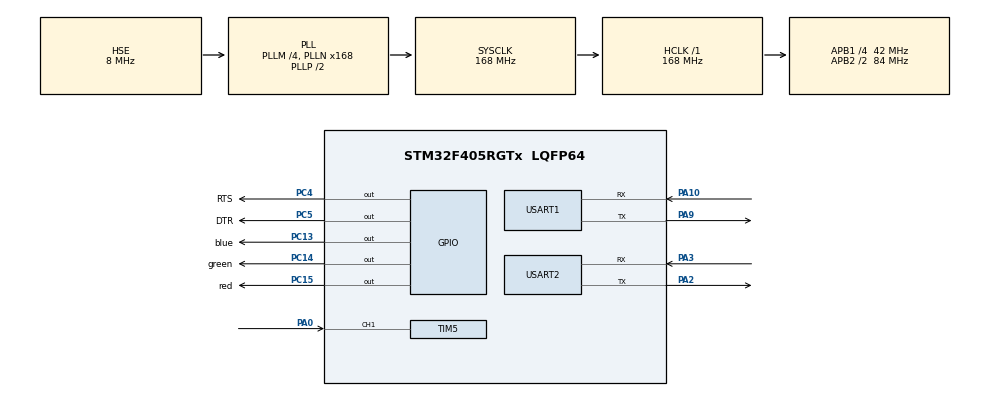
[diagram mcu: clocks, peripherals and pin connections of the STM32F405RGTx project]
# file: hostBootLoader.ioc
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Dma.Request0=USART1_TX
Dma.Request1=USART1_RX
Dma.Request2=USART2_TX
Dma.Request3=USART2_RX
Dma.USART1_RX.1.Direction=DMA_PERIPH_TO_MEMORY
Dma.USART1_RX.1.FIFOMode=DMA_FIFOMODE_DISABLE
Dma.USART1_RX.1.Instance=DMA2_Stream2
Dma.USART1_RX.1.MemDataAlignment=DMA_MDATAALIGN_BYTE
Dma.USART1_RX.1.MemInc=DMA_MINC_ENABLE
Dma.USART1_RX.1.Mode=DMA_NORMAL
Dma.USART1_RX.1.PeriphDataAlignment=DMA_PDATAALIGN_BYTE
Dma.USART1_RX.1.PeriphInc=DMA_PINC_DISABLE
Dma.USART1_RX.1.Priority=DMA_PRIORITY_LOW
Dma.USART1_TX.0.Direction=DMA_MEMORY_TO_PERIPH
Dma.USART1_TX.0.FIFOMode=DMA_FIFOMODE_DISABLE
Dma.USART1_TX.0.Instance=DMA2_Stream7
Dma.USART1_TX.0.MemDataAlignment=DMA_MDATAALIGN_BYTE
Dma.USART1_TX.0.MemInc=DMA_MINC_ENABLE
Dma.USART1_TX.0.Mode=DMA_NORMAL
Dma.USART1_TX.0.PeriphDataAlignment=DMA_PDATAALIGN_BYTE
Dma.USART1_TX.0.PeriphInc=DMA_PINC_DISABLE
Dma.USART1_TX.0.Priority=DMA_PRIORITY_LOW
Dma.USART2_RX.3.Direction=DMA_PERIPH_TO_MEMORY
Dma.USART2_RX.3.FIFOMode=DMA_FIFOMODE_DISABLE
Dma.USART2_RX.3.Instance=DMA1_Stream5
Dma.USART2_RX.3.MemDataAlignment=DMA_MDATAALIGN_BYTE
Dma.USART2_RX.3.MemInc=DMA_MINC_ENABLE
Dma.USART2_RX.3.Mode=DMA_NORMAL
Dma.USART2_RX.3.PeriphDataAlignment=DMA_PDATAALIGN_BYTE
Dma.USART2_RX.3.PeriphInc=DMA_PINC_DISABLE
Dma.USART2_RX.3.Priority=DMA_PRIORITY_HIGH
Dma.USART2_TX.2.Direction=DMA_MEMORY_TO_PERIPH
Dma.USART2_TX.2.FIFOMode=DMA_FIFOMODE_DISABLE
Dma.USART2_TX.2.Instance=DMA1_Stream6
Dma.USART2_TX.2.MemDataAlignment=DMA_MDATAALIGN_BYTE
Dma.USART2_TX.2.MemInc=DMA_MINC_ENABLE
Dma.USART2_TX.2.Mode=DMA_NORMAL
Dma.USART2_TX.2.PeriphDataAlignment=DMA_PDATAALIGN_BYTE
Dma.USART2_TX.2.PeriphInc=DMA_PINC_DISABLE
Dma.USART2_TX.2.Priority=DMA_PRIORITY_HIGH
Mcu.Family=STM32F4
Mcu.Name=STM32F405RGTx
Mcu.Package=LQFP64
NVIC.DMA1_Stream5_IRQn=true\:0\:0\:false\:false\:true\:false\:true
NVIC.DMA1_Stream6_IRQn=true\:0\:0\:false\:false\:true\:false\:true
NVIC.DMA2_Stream2_IRQn=true\:0\:0\:false\:false\:true\:false\:true
NVIC.DMA2_Stream7_IRQn=true\:0\:0\:false\:false\:true\:false\:true
NVIC.PriorityGroup=NVIC_PRIORITYGROUP_4
NVIC.TIM5_IRQn=true\:0\:0\:false\:false\:true\:true\:true
NVIC.USART1_IRQn=true\:0\:0\:false\:false\:true\:true\:true
NVIC.USART2_IRQn=true\:0\:0\:false\:false\:true\:true\:true
PA0-WKUP.Signal=S_TIM5_CH1
PA10.Mode=Asynchronous
PA10.Signal=USART1_RX
PA13.Mode=Serial_Wire
PA13.Signal=SYS_JTMS-SWDIO
PA14.Mode=Serial_Wire
PA14.Signal=SYS_JTCK-SWCLK
PA2.GPIO_ModeDefaultPP=GPIO_MODE_AF_PP
PA2.GPIO_PuPd=GPIO_NOPULL
PA2.GPIO_Speed=GPIO_SPEED_FREQ_VERY_HIGH
PA2.Mode=Asynchronous
PA2.Signal=USART2_TX
PA3.GPIO_ModeDefaultPP=GPIO_MODE_AF_PP
PA3.GPIO_PuPd=GPIO_NOPULL
PA3.GPIO_Speed=GPIO_SPEED_FREQ_VERY_HIGH
PA3.Mode=Asynchronous
PA3.Signal=USART2_RX
PA9.Mode=Asynchronous
PA9.Signal=USART1_TX
PC13-ANTI_TAMP.GPIO_Label=blue
PC13-ANTI_TAMP.GPIO_ModeDefaultOutputPP=GPIO_MODE_OUTPUT_PP
PC13-ANTI_TAMP.GPIO_PuPd=GPIO_NOPULL
PC13-ANTI_TAMP.GPIO_Speed=GPIO_SPEED_FREQ_LOW
PC13-ANTI_TAMP.PinState=GPIO_PIN_SET
PC13-ANTI_TAMP.Signal=GPIO_Output
PC14-OSC32_IN.GPIO_Label=green
PC14-OSC32_IN.GPIO_ModeDefaultOutputPP=GPIO_MODE_OUTPUT_PP
PC14-OSC32_IN.GPIO_PuPd=GPIO_NOPULL
PC14-OSC32_IN.GPIO_Speed=GPIO_SPEED_FREQ_LOW
PC14-OSC32_IN.PinState=GPIO_PIN_SET
PC14-OSC32_IN.Signal=GPIO_Output
PC15-OSC32_OUT.GPIO_Label=red
PC15-OSC32_OUT.GPIO_ModeDefaultOutputPP=GPIO_MODE_OUTPUT_PP
PC15-OSC32_OUT.GPIO_PuPd=GPIO_NOPULL
PC15-OSC32_OUT.GPIO_Speed=GPIO_SPEED_FREQ_LOW
PC15-OSC32_OUT.PinState=GPIO_PIN_SET
PC15-OSC32_OUT.Signal=GPIO_Output
PC4.GPIO_Label=RTS
PC4.GPIO_ModeDefaultOutputPP=GPIO_MODE_OUTPUT_PP
PC4.GPIO_PuPd=GPIO_NOPULL
PC4.GPIO_Speed=GPIO_SPEED_FREQ_VERY_HIGH
PC4.PinState=GPIO_PIN_SET
PC4.Signal=GPIO_Output
PC5.GPIO_Label=DTR
PC5.GPIO_ModeDefaultOutputPP=GPIO_MODE_OUTPUT_PP
PC5.GPIO_PuPd=GPIO_NOPULL
PC5.GPIO_Speed=GPIO_SPEED_FREQ_VERY_HIGH
PC5.PinState=GPIO_PIN_RESET
PC5.Signal=GPIO_Output
PH0-OSC_IN.Mode=HSE-External-Oscillator
PH0-OSC_IN.Signal=RCC_OSC_IN
PH1-OSC_OUT.Mode=HSE-External-Oscillator
PH1-OSC_OUT.Signal=RCC_OSC_OUT
ProjectManager.HeapSize=0x200
ProjectManager.StackSize=0x400
ProjectManager.TargetToolchain=MDK-ARM V5.32
RCC.48MHZClocksFreq_Value=84000000
RCC.AHBFreq_Value=168000000
RCC.APB1CLKDivider=RCC_HCLK_DIV4
RCC.APB1Freq_Value=42000000
RCC.APB1TimFreq_Value=84000000
RCC.APB2CLKDivider=RCC_HCLK_DIV2
RCC.APB2Freq_Value=84000000
RCC.APB2TimFreq_Value=168000000
RCC.CortexFreq_Value=168000000
RCC.HCLKFreq_Value=168000000
RCC.HSE_VALUE=8000000
RCC.HSI_VALUE=16000000
RCC.LSE_VALUE=32768
RCC.PLLM=4
RCC.PLLN=168
RCC.PLLSourceVirtual=RCC_PLLSOURCE_HSE
RCC.SYSCLKFreq_VALUE=168000000
RCC.SYSCLKSource=RCC_SYSCLKSOURCE_PLLCLK
RCC.VCOOutputFreq_Value=336000000
SH.S_TIM5_CH1.0=TIM5_CH1,Input_Capture1_from_TI1
TIM2.Prescaler=83
TIM5.Channel-Input_Capture1_from_TI1=TIM_CHANNEL_1
TIM5.Prescaler=83
USART1.VirtualMode=VM_ASYNC
USART2.Parity=PARITY_EVEN
USART2.VirtualMode=VM_ASYNC
USART2.WordLength=WORDLENGTH_9B
VP_TIM2_VS_ClockSourceINT.Mode=Internal
VP_TIM5_VS_ClockSourceINT.Mode=Internal
board=custom

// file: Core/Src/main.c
/* USER CODE BEGIN Header */
/**
  ******************************************************************************
  * @file           : main.c
  * @brief          : Main program body
  ******************************************************************************
  * @attention
  *
  * <h2><center>&copy; Copyright (c) 2022 STMicroelectronics.
  * All rights reserved.</center></h2>
  *
  * This software component is licensed by ST under BSD 3-Clause license,
  * the "License"; You may not use this file except in compliance with the
  * License. You may obtain a copy of the License at:
  *                        opensource.org/licenses/BSD-3-Clause
  *
  ******************************************************************************
  */
/* USER CODE END Header */
#include "main.h"

/* USER CODE BEGIN Includes */
#include "hostBootLoader.h"
#include "test.h"
/* USER CODE END Includes */

TIM_HandleTypeDef htim2;
TIM_HandleTypeDef htim5;

UART_HandleTypeDef huart1;
UART_HandleTypeDef huart2;
DMA_HandleTypeDef hdma_usart1_tx;
DMA_HandleTypeDef hdma_usart1_rx;
DMA_HandleTypeDef hdma_usart2_tx;
DMA_HandleTypeDef hdma_usart2_rx;

void SystemClock_Config(void);
static void MX_GPIO_Init(void);
static void MX_DMA_Init(void);
static void MX_TIM2_Init(void);
static void MX_USART1_UART_Init(void);
static void MX_USART2_UART_Init(void);
static void MX_TIM5_Init(void);

int main(void)
{

  /* MCU Configuration--------------------------------------------------------*/

  /* Reset of all peripherals, Initializes the Flash interface and the Systick. */
  HAL_Init();

  /* Configure the system clock */
  SystemClock_Config();

  /* Initialize all configured peripherals */
  MX_GPIO_Init();
  MX_DMA_Init();
  MX_TIM2_Init();
  MX_USART1_UART_Init();
  MX_USART2_UART_Init();
  MX_TIM5_Init();
  /* USER CODE BEGIN 2 */
    hostBootLoader_init(&huart2, &huart1);
  /* USER CODE END 2 */

  /* Infinite loop */
  /* USER CODE BEGIN WHILE */
  while (1)
  {

      hostBootLoader_process();
    /* USER CODE END WHILE */

  }
}

void SystemClock_Config(void)
{
  RCC_OscInitTypeDef RCC_OscInitStruct = {0};
  RCC_ClkInitTypeDef RCC_ClkInitStruct = {0};

  /** Configure the main internal regulator output voltage
  */
  __HAL_RCC_PWR_CLK_ENABLE();
  __HAL_PWR_VOLTAGESCALING_CONFIG(PWR_REGULATOR_VOLTAGE_SCALE1);
  /** Initializes the RCC Oscillators according to the specified parameters
  * in the RCC_OscInitTypeDef structure.
  */
  RCC_OscInitStruct.OscillatorType = RCC_OSCILLATORTYPE_HSE;
  RCC_OscInitStruct.HSEState = RCC_HSE_ON;
  RCC_OscInitStruct.PLL.PLLState = RCC_PLL_ON;
  RCC_OscInitStruct.PLL.PLLSource = RCC_PLLSOURCE_HSE;
  RCC_OscInitStruct.PLL.PLLM = 4;
  RCC_OscInitStruct.PLL.PLLN = 168;
  RCC_OscInitStruct.PLL.PLLP = RCC_PLLP_DIV2;
  RCC_OscInitStruct.PLL.PLLQ = 4;
  if (HAL_RCC_OscConfig(&RCC_OscInitStruct) != HAL_OK)
  {
    Error_Handler();
  }
  /** Initializes the CPU, AHB and APB buses clocks
  */
  RCC_ClkInitStruct.ClockType = RCC_CLOCKTYPE_HCLK|RCC_CLOCKTYPE_SYSCLK
                              |RCC_CLOCKTYPE_PCLK1|RCC_CLOCKTYPE_PCLK2;
  RCC_ClkInitStruct.SYSCLKSource = RCC_SYSCLKSOURCE_PLLCLK;
  RCC_ClkInitStruct.AHBCLKDivider = RCC_SYSCLK_DIV1;
  RCC_ClkInitStruct.APB1CLKDivider = RCC_HCLK_DIV4;
  RCC_ClkInitStruct.APB2CLKDivider = RCC_HCLK_DIV2;

  if (HAL_RCC_ClockConfig(&RCC_ClkInitStruct, FLASH_LATENCY_5) != HAL_OK)
  {
    Error_Handler();
  }
}

static void MX_TIM2_Init(void)
{

  TIM_ClockConfigTypeDef sClockSourceConfig = {0};
  TIM_MasterConfigTypeDef sMasterConfig = {0};

  htim2.Instance = TIM2;
  htim2.Init.Prescaler = 83;
  htim2.Init.CounterMode = TIM_COUNTERMODE_UP;
  htim2.Init.Period = 4294967295;
  htim2.Init.ClockDivision = TIM_CLOCKDIVISION_DIV1;
  htim2.Init.AutoReloadPreload = TIM_AUTORELOAD_PRELOAD_DISABLE;
  if (HAL_TIM_Base_Init(&htim2) != HAL_OK)
  {
    Error_Handler();
  }
  sClockSourceConfig.ClockSource = TIM_CLOCKSOURCE_INTERNAL;
  if (HAL_TIM_ConfigClockSource(&htim2, &sClockSourceConfig) != HAL_OK)
  {
    Error_Handler();
  }
  sMasterConfig.MasterOutputTrigger = TIM_TRGO_RESET;
  sMasterConfig.MasterSlaveMode = TIM_MASTERSLAVEMODE_DISABLE;
  if (HAL_TIMEx_MasterConfigSynchronization(&htim2, &sMasterConfig) != HAL_OK)
  {
    Error_Handler();
  }

}

static void MX_TIM5_Init(void)
{

  TIM_ClockConfigTypeDef sClockSourceConfig = {0};
  TIM_MasterConfigTypeDef sMasterConfig = {0};
  TIM_IC_InitTypeDef sConfigIC = {0};

  htim5.Instance = TIM5;
  htim5.Init.Prescaler = 83;
  htim5.Init.CounterMode = TIM_COUNTERMODE_UP;
  htim5.Init.Period = 4294967295;
  htim5.Init.ClockDivision = TIM_CLOCKDIVISION_DIV1;
  htim5.Init.AutoReloadPreload = TIM_AUTORELOAD_PRELOAD_DISABLE;
  if (HAL_TIM_Base_Init(&htim5) != HAL_OK)
  {
    Error_Handler();
  }
  sClockSourceConfig.ClockSource = TIM_CLOCKSOURCE_INTERNAL;
  if (HAL_TIM_ConfigClockSource(&htim5, &sClockSourceConfig) != HAL_OK)
  {
    Error_Handler();
  }
  if (HAL_TIM_IC_Init(&htim5) != HAL_OK)
  {
    Error_Handler();
  }
  sMasterConfig.MasterOutputTrigger = TIM_TRGO_RESET;
  sMasterConfig.MasterSlaveMode = TIM_MASTERSLAVEMODE_DISABLE;
  if (HAL_TIMEx_MasterConfigSynchronization(&htim5, &sMasterConfig) != HAL_OK)
  {
    Error_Handler();
  }
  sConfigIC.ICPolarity = TIM_INPUTCHANNELPOLARITY_RISING;
  sConfigIC.ICSelection = TIM_ICSELECTION_DIRECTTI;
  sConfigIC.ICPrescaler = TIM_ICPSC_DIV1;
  sConfigIC.ICFilter = 0;
  if (HAL_TIM_IC_ConfigChannel(&htim5, &sConfigIC, TIM_CHANNEL_1) != HAL_OK)
  {
    Error_Handler();
  }

}

static void MX_USART1_UART_Init(void)
{

  huart1.Instance = USART1;
  huart1.Init.BaudRate = 115200;
  huart1.Init.WordLength = UART_WORDLENGTH_8B;
  huart1.Init.StopBits = UART_STOPBITS_1;
  huart1.Init.Parity = UART_PARITY_NONE;
  huart1.Init.Mode = UART_MODE_TX_RX;
  huart1.Init.HwFlowCtl = UART_HWCONTROL_NONE;
  huart1.Init.OverSampling = UART_OVERSAMPLING_16;
  if (HAL_UART_Init(&huart1) != HAL_OK)
  {
    Error_Handler();
  }

}

static void MX_USART2_UART_Init(void)
{

  huart2.Instance = USART2;
  huart2.Init.BaudRate = 115200;
  huart2.Init.WordLength = UART_WORDLENGTH_9B;
  huart2.Init.StopBits = UART_STOPBITS_1;
  huart2.Init.Parity = UART_PARITY_EVEN;
  huart2.Init.Mode = UART_MODE_TX_RX;
  huart2.Init.HwFlowCtl = UART_HWCONTROL_NONE;
  huart2.Init.OverSampling = UART_OVERSAMPLING_16;
  if (HAL_UART_Init(&huart2) != HAL_OK)
  {
    Error_Handler();
  }

}

static void MX_DMA_Init(void)
{

  /* DMA controller clock enable */
  __HAL_RCC_DMA2_CLK_ENABLE();
  __HAL_RCC_DMA1_CLK_ENABLE();

  /* DMA interrupt init */
  /* DMA1_Stream5_IRQn interrupt configuration */
  HAL_NVIC_SetPriority(DMA1_Stream5_IRQn, 0, 0);
  HAL_NVIC_EnableIRQ(DMA1_Stream5_IRQn);
  /* DMA1_Stream6_IRQn interrupt configuration */
  HAL_NVIC_SetPriority(DMA1_Stream6_IRQn, 0, 0);
  HAL_NVIC_EnableIRQ(DMA1_Stream6_IRQn);
  /* DMA2_Stream2_IRQn interrupt configuration */
  HAL_NVIC_SetPriority(DMA2_Stream2_IRQn, 0, 0);
  HAL_NVIC_EnableIRQ(DMA2_Stream2_IRQn);
  /* DMA2_Stream7_IRQn interrupt configuration */
  HAL_NVIC_SetPriority(DMA2_Stream7_IRQn, 0, 0);
  HAL_NVIC_EnableIRQ(DMA2_Stream7_IRQn);

}

static void MX_GPIO_Init(void)
{
  GPIO_InitTypeDef GPIO_InitStruct = {0};

  /* GPIO Ports Clock Enable */
  __HAL_RCC_GPIOC_CLK_ENABLE();
  __HAL_RCC_GPIOH_CLK_ENABLE();
  __HAL_RCC_GPIOA_CLK_ENABLE();

  /*Configure GPIO pin Output Level */
  HAL_GPIO_WritePin(GPIOC, blue_Pin|green_Pin|red_Pin|RTS_Pin, GPIO_PIN_SET);

  /*Configure GPIO pin Output Level */
  HAL_GPIO_WritePin(DTR_GPIO_Port, DTR_Pin, GPIO_PIN_RESET);

  /*Configure GPIO pins : blue_Pin green_Pin red_Pin */
  GPIO_InitStruct.Pin = blue_Pin|green_Pin|red_Pin;
  GPIO_InitStruct.Mode = GPIO_MODE_OUTPUT_PP;
  GPIO_InitStruct.Pull = GPIO_NOPULL;
  GPIO_InitStruct.Speed = GPIO_SPEED_FREQ_LOW;
  HAL_GPIO_Init(GPIOC, &GPIO_InitStruct);

  /*Configure GPIO pins : RTS_Pin DTR_Pin */
  GPIO_InitStruct.Pin = RTS_Pin|DTR_Pin;
  GPIO_InitStruct.Mode = GPIO_MODE_OUTPUT_PP;
  GPIO_InitStruct.Pull = GPIO_NOPULL;
  GPIO_InitStruct.Speed = GPIO_SPEED_FREQ_VERY_HIGH;
  HAL_GPIO_Init(GPIOC, &GPIO_InitStruct);

  GPIO_InitStruct.Pin = GPIO_PIN_6|GPIO_PIN_7;
  HAL_GPIO_Init(GPIOA, &GPIO_InitStruct);

  HAL_GPIO_WritePin(GPIOA, GPIO_PIN_6, GPIO_PIN_RESET);
  HAL_GPIO_WritePin(GPIOA, GPIO_PIN_7, GPIO_PIN_SET);
}

void Error_Handler(void)
{
  __disable_irq();
  while (1)
  {
  }
}

/************************ (C) COPYRIGHT STMicroelectronics *****END OF FILE****/
